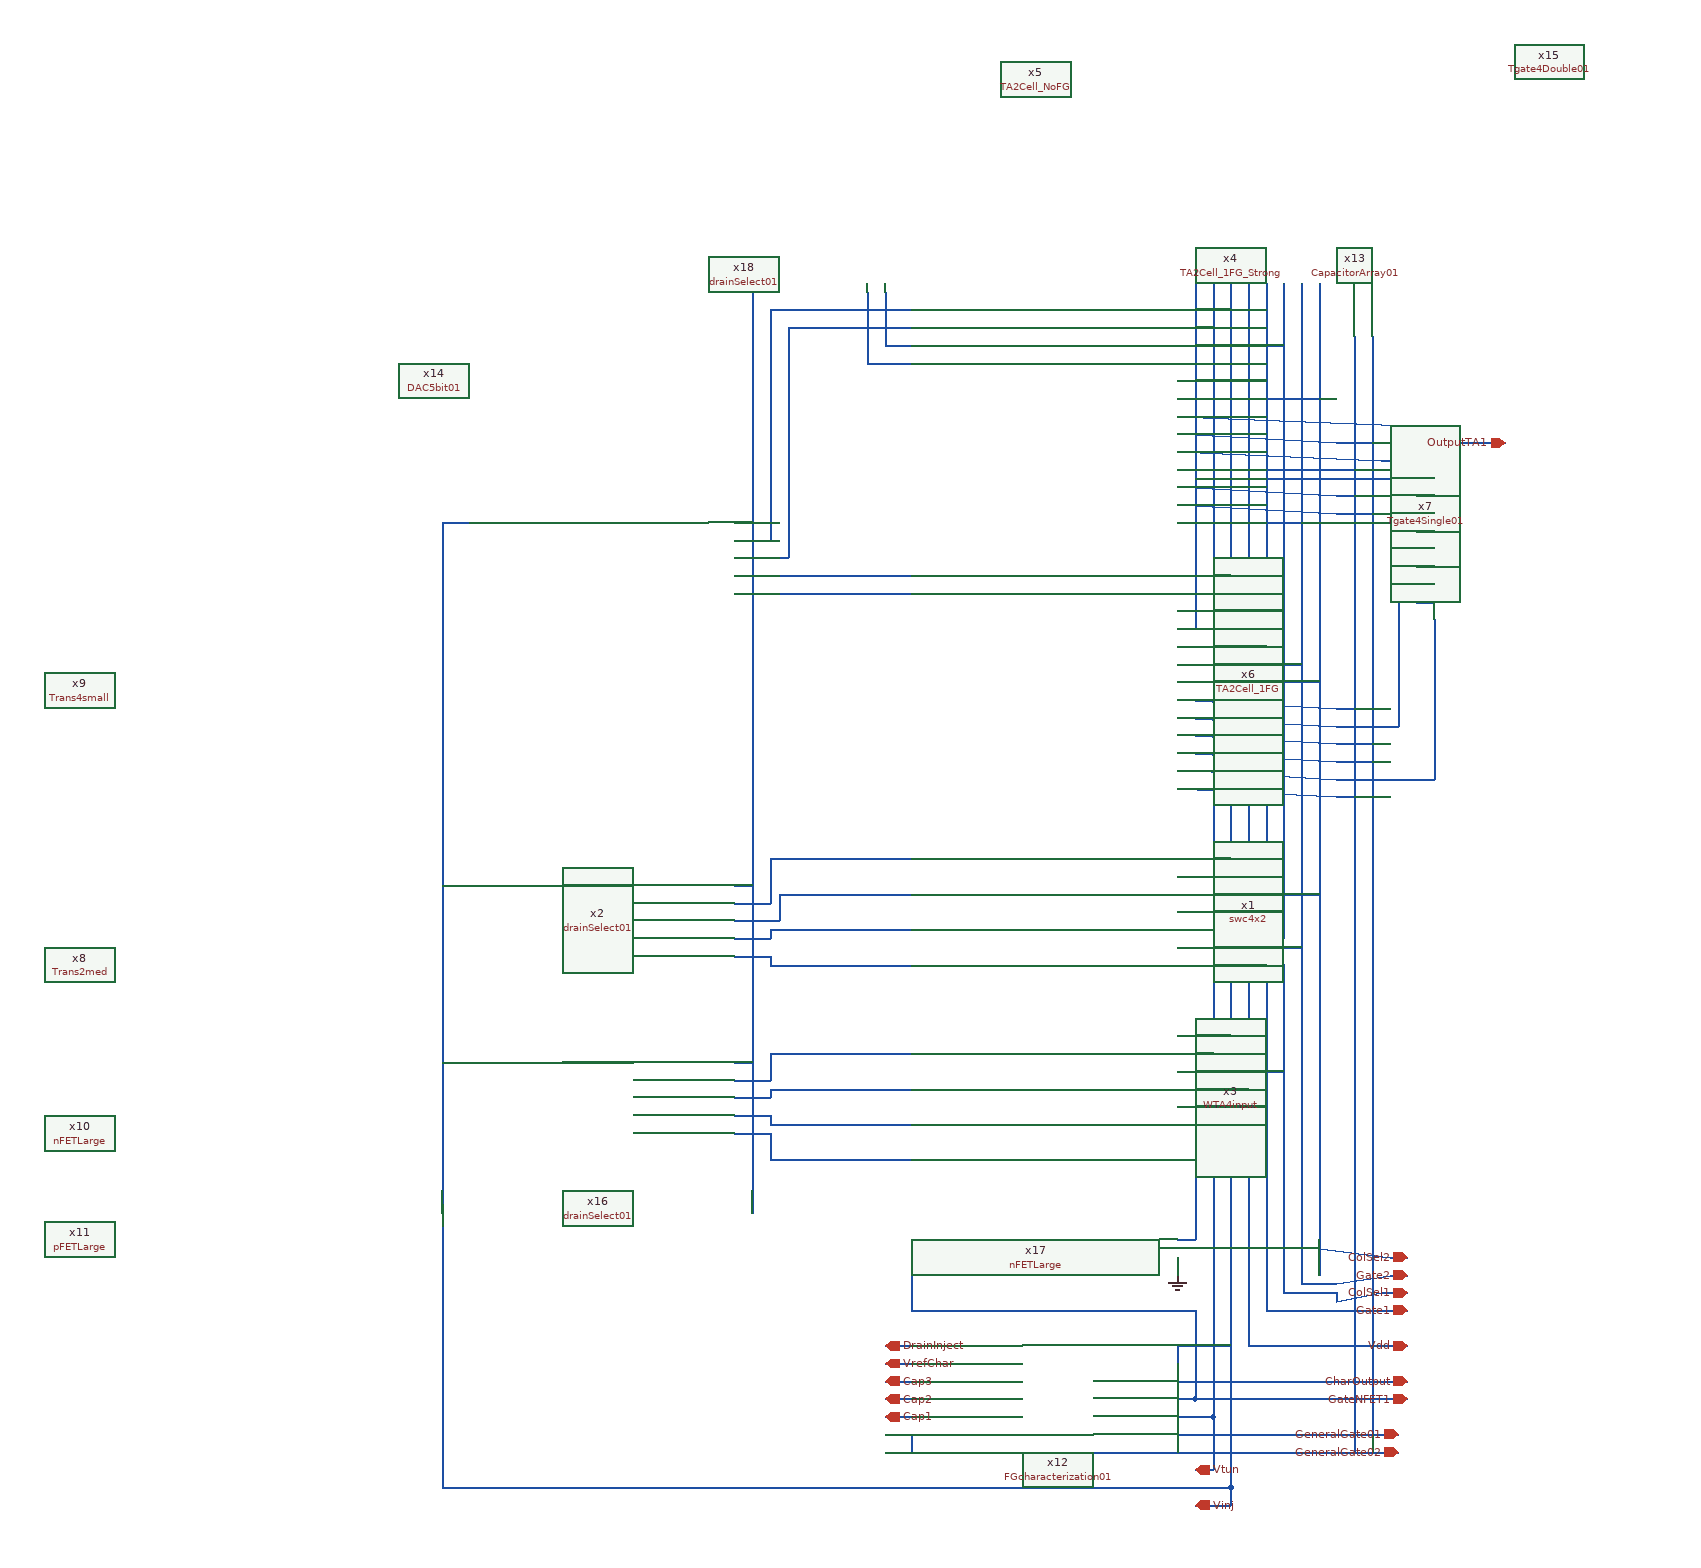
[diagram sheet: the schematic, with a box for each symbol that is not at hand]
v {xschem version=2.9.9 file_version=1.2 }
G {}
K {}
V {}
S {}
E {}
N 370 -10 370 440 { lab=Vtun}
N -500 -10 -500 430 { lab=Vinj}
N 390 -10 390 440 { lab=Vinj}
N -500 60 -470 60 { lab=Vinj}
N -500 260 -470 260 { lab=Vinj}
N 330 30 390 30 { lab=Vinj}
N 330 230 390 230 { lab=Vinj}
N 330 50 370 50 { lab=Vtun}
N 330 250 370 250 { lab=Vtun}
N 410 -10 410 440 { lab=Vdd}
N 330 290 410 290 { lab=Vdd}
N 330 480 330 500 { lab=GND}
N 330 330 350 330 { lab=#net1}
N 350 330 350 460 { lab=#net1}
N 330 460 350 460 { lab=#net1}
N -150 -10 -150 430 { lab=#net2}
N -170 60 -150 60 { lab=#net2}
N -170 260 -150 260 { lab=#net2}
N -130 30 30 30 { lab=#net3}
N -130 30 -130 80 { lab=#net3}
N -170 80 -130 80 { lab=#net3}
N -130 150 30 150 { lab=#net4}
N -130 140 -130 150 { lab=#net4}
N -170 140 -130 140 { lab=#net4}
N -130 110 30 110 { lab=#net5}
N -130 110 -130 120 { lab=#net5}
N -170 120 -130 120 { lab=#net5}
N -120 70 30 70 { lab=#net6}
N -120 70 -120 100 { lab=#net6}
N -170 100 -120 100 { lab=#net6}
N -130 250 30 250 { lab=#net7}
N -130 370 30 370 { lab=#net8}
N -110 330 30 330 { lab=#net9}
N -110 290 30 290 { lab=#net10}
N -170 280 -130 280 { lab=#net7}
N -130 250 -130 280 { lab=#net7}
N -170 340 -130 340 { lab=#net8}
N -130 340 -130 370 { lab=#net8}
N -130 330 -110 330 { lab=#net9}
N -130 320 -130 330 { lab=#net9}
N -170 320 -130 320 { lab=#net9}
N -130 290 -110 290 { lab=#net10}
N -130 290 -130 300 { lab=#net10}
N -170 300 -130 300 { lab=#net10}
N 430 -10 430 500 { lab=#net11}
N 470 -10 470 500 { lab=#net12}
N 330 310 430 310 { lab=#net11}
N 330 150 430 150 { lab=#net11}
N 330 130 450 130 { lab=#net12}
N 490 -10 490 500 { lab=#net13}
N 450 130 470 130 { lab=#net12}
N 450 -10 450 120 { lab=#net14}
N 450 150 450 500 { lab=#net14}
N 330 90 450 90 { lab=#net14}
N 330 270 450 270 { lab=#net14}
N 330 70 490 70 { lab=#net13}
N 440 120 450 150 { lab=#net14}
N 440 120 450 120 { lab=#net14}
N -500 420 -500 550 { lab=Vinj}
N -500 740 390 740 { lab=Vinj}
N 390 440 390 550 { lab=Vinj}
N 390 550 390 720 { lab=Vinj}
N -500 550 -500 720 { lab=Vinj}
N 370 440 370 660 { lab=Vtun}
N 330 660 370 660 { lab=Vtun}
N 330 580 390 580 { lab=Vinj}
N 390 720 390 740 { lab=Vinj}
N 370 660 370 720 { lab=Vtun}
N 350 720 370 720 { lab=Vtun}
N 390 740 390 760 { lab=Vinj}
N 350 760 390 760 { lab=Vinj}
N 30 460 30 540 { lab=GateNFET1}
N 30 540 350 540 { lab=GateNFET1}
N 350 540 350 640 { lab=GateNFET1}
N 330 640 350 640 { lab=GateNFET1}
N 350 640 590 640 { lab=GateNFET1}
N 330 620 570 620 { lab=CharOutput}
N 330 580 330 600 { lab=Vinj}
N 0 700 330 700 { lab=GeneralGate02}
N -0 680 30 680 { lab=GeneralGate02}
N -0 660 30 660 { lab=Cap1}
N -0 640 30 640 { lab=Cap2}
N -0 620 30 620 { lab=Cap3}
N -0 600 30 600 { lab=VrefChar}
N 0 580 30 580 { lab=DrainInject}
N 370 -520 370 -70 { lab=Vtun}
N 390 -520 390 -70 { lab=Vinj}
N 410 -520 410 -70 { lab=Vdd}
N 430 -520 430 -10 { lab=#net11}
N 470 -520 470 -10 { lab=#net12}
N 490 -520 490 -10 { lab=#net13}
N 450 -520 450 -10 { lab=#net14}
N 370 -70 370 -10 { lab=Vtun}
N 390 -70 390 -10 { lab=Vinj}
N 410 -70 410 -10 { lab=Vdd}
N -150 -450 -150 -10 { lab=#net2}
N -150 -610 -150 -450 { lab=#net2}
N -170 -350 -150 -350 { lab=#net2}
N -130 -270 30 -270 { lab=#net15}
N -130 -290 30 -290 { lab=#net16}
N -170 -290 -130 -290 { lab=#net16}
N -170 -270 -130 -270 { lab=#net15}
N -500 -350 -500 -10 { lab=Vinj}
N -500 -350 -470 -350 { lab=Vinj}
N -0 -610 -0 -550 { lab=#net17}
N -20 -610 -20 -530 { lab=#net18}
N 0 -550 30 -550 { lab=#net17}
N -20 -530 30 -530 { lab=#net18}
N -170 -330 -130 -330 { lab=#net19}
N -130 -590 -130 -330 { lab=#net19}
N -130 -590 30 -590 { lab=#net19}
N -170 -310 -110 -310 { lab=#net20}
N -110 -570 -110 -310 { lab=#net20}
N -110 -570 30 -570 { lab=#net20}
N 370 -620 370 -520 { lab=Vtun}
N 390 -620 390 -520 { lab=Vinj}
N 410 -620 410 -520 { lab=Vdd}
N 430 -620 430 -520 { lab=#net11}
N 450 -620 450 -520 { lab=#net14}
N 470 -620 470 -520 { lab=#net12}
N 490 -620 490 -520 { lab=#net13}
N 330 -590 390 -590 { lab=Vinj}
N 330 -570 370 -570 { lab=Vtun}
N 330 -290 390 -290 { lab=Vinj}
N 330 -270 370 -270 { lab=Vtun}
N 330 -250 450 -250 { lab=#net14}
N 330 -550 450 -550 { lab=#net14}
N 330 -490 490 -490 { lab=#net13}
N 330 -170 490 -170 { lab=#net13}
N 330 -510 430 -510 { lab=#net11}
N 330 -210 430 -210 { lab=#net11}
N 330 -190 470 -190 { lab=#net12}
N 330 -350 470 -350 { lab=#net12}
N 350 -620 350 -230 { lab=#net21}
N 330 -230 350 -230 { lab=#net21}
N 330 -530 350 -530 { lab=#net21}
N 600 -440 600 -260 { lab=OutputTA1}
N 600 -260 620 -260 { lab=OutputTA1}
N 600 -300 620 -300 { lab=OutputTA1}
N 600 -340 620 -340 { lab=OutputTA1}
N 600 -380 620 -380 { lab=OutputTA1}
N 350 -400 620 -400 { lab=#net21}
N 620 -240 620 -60 { lab=#net22}
N 330 -70 350 -70 { lab=#net22}
N 350 -70 510 -60 { lab=#net22}
N 510 -60 620 -60 { lab=#net22}
N 330 -130 510 -120 { lab=#net23}
N 510 -120 580 -120 { lab=#net23}
N 580 -280 580 -120 { lab=#net23}
N 580 -280 620 -280 { lab=#net23}
N 590 -460 590 -360 { lab=#net24}
N 330 -470 590 -460 { lab=#net24}
N 330 -430 560 -420 { lab=#net25}
N 590 -360 620 -360 { lab=#net24}
N 580 -320 620 -320 { lab=#net25}
N 580 -420 580 -320 { lab=#net25}
N 560 -420 580 -420 { lab=#net25}
N 600 -440 680 -440 { lab=OutputTA1}
N 680 -440 700 -440 { lab=OutputTA1}
N 330 680 580 680 { lab=GeneralGate01}
N 330 700 580 700 { lab=GeneralGate02}
N 30 680 30 700 { lab=GeneralGate02}
N 570 620 590 620 { lab=CharOutput}
N 530 -560 530 520 { lab=GeneralGate02}
N 550 -560 550 520 { lab=GeneralGate01}
N 550 520 550 680 { lab=GeneralGate01}
N 530 520 530 700 { lab=GeneralGate02}
N 410 440 410 580 { lab=Vdd}
N 410 580 590 580 { lab=Vdd}
N -500 720 -500 740 { lab=Vinj}
N 330 -50 510 -40 { lab=GeneralGate02}
N 510 -40 530 -40 { lab=GeneralGate02}
N 330 -90 510 -80 { lab=GeneralGate01}
N 510 -80 550 -80 { lab=GeneralGate01}
N 330 -110 510 -100 { lab=GeneralGate01}
N 510 -100 550 -100 { lab=GeneralGate01}
N 330 -150 510 -140 { lab=GeneralGate02}
N 510 -140 530 -140 { lab=GeneralGate02}
N 330 -450 510 -440 { lab=GeneralGate01}
N 510 -440 550 -440 { lab=GeneralGate01}
N 330 -370 510 -360 { lab=GeneralGate01}
N 510 -360 550 -360 { lab=GeneralGate01}
N 330 -390 510 -380 { lab=GeneralGate02}
N 510 -380 530 -380 { lab=GeneralGate02}
N 330 -410 530 -410 { lab=GeneralGate02}
N 430 540 590 540 {}
N 430 500 430 540 {}
N 450 500 450 520 {}
N 450 520 510 520 {}
N 470 500 470 510 {}
N 470 510 510 510 {}
N 570 480 590 480 {}
N 490 470 570 480 {}
N 570 500 590 500 {}
N 510 510 570 500 {}
N 560 520 590 520 {}
N 510 530 560 520 {}
N 510 520 510 530 {}
C {swc4x2.sym} 180 100 0 0 {name=x1}
C {drainSelect01.sym} -320 100 0 0 {name=x2}
C {WTA4input.sym} 180 320 0 0 {name=x3}
C {TA2Cell_1FG_Strong.sym} 180 -470 0 0 {name=x4}
C {TA2Cell_NoFG.sym} 170 -850 0 0 {name=x5}
C {TA2Cell_1FG.sym} 180 -170 0 0 {name=x6}
C {Tgate4Single01.sym} 770 -320 0 1 {name=x7}
C {Trans2med.sym} -910 150 0 0 {name=x8}
C {Trans4small.sym} -910 -160 0 0 {name=x9}
C {nFETLarge.sym} -910 340 0 0 {name=x10}
C {pFETLarge.sym} -910 460 0 0 {name=x11}
C {FGcharacterization01.sym} 180 630 0 0 {name=x12}
C {CapacitorArray01.sym} 750 -630 0 0 {name=x13}
C {DAC5bit01.sym} -510 -510 0 0 {name=x14}
C {Tgate4Double01.sym} 750 -870 0 0 {name=x15}
C {drainSelect01.sym} -320 300 0 0 {name=x16}
C {devices/gnd.sym} 330 500 0 0 {name=l1 lab=GND}
C {nFETLarge.sym} 180 470 0 0 {name=x17}
C {drainSelect01.sym} -320 -310 0 0 {name=x18}
C {devices/iopin.sym} 350 720 0 1 {name=Vtun lab=Vtun}
C {devices/iopin.sym} 350 760 0 1 {name=Vinj lab=Vinj}
C {devices/iopin.sym} 590 640 0 0 {name=GateNFET1 lab=GateNFET1}
C {devices/iopin.sym} 590 620 0 0 {name=CharOutput lab=CharOutput}
C {devices/iopin.sym} 0 580 0 1 {name=DrainInject lab=DrainInject}
C {devices/iopin.sym} 0 600 0 1 {name=VrefChar lab=VrefChar}
C {devices/iopin.sym} 0 620 0 1 {name=Cap3 lab=Cap3}
C {devices/iopin.sym} 0 640 0 1 {name=Cap2 lab=Cap2}
C {devices/iopin.sym} 0 660 0 1 {name=Cap1 lab=Cap1}
C {devices/iopin.sym} 580 680 0 0 {name=GeneralGate01 lab=GeneralGate01}
C {devices/iopin.sym} 580 700 0 0 {name=GeneralGate02 lab=GeneralGate02}
C {devices/iopin.sym} 700 -440 0 0 {name=OutputTA1 lab=OutputTA1}
C {devices/iopin.sym} 590 580 0 0 {name=Vdd lab=Vdd}
C {devices/iopin.sym} 590 540 0 0 {name=Gate1 lab=Gate1}
C {devices/iopin.sym} 590 520 0 0 {name=ColSel1 lab=ColSel1}
C {devices/iopin.sym} 590 500 0 0 {name=Gate2 lab=Gate2}
C {devices/iopin.sym} 590 480 0 0 {name=ColSel2 lab=ColSel2}
